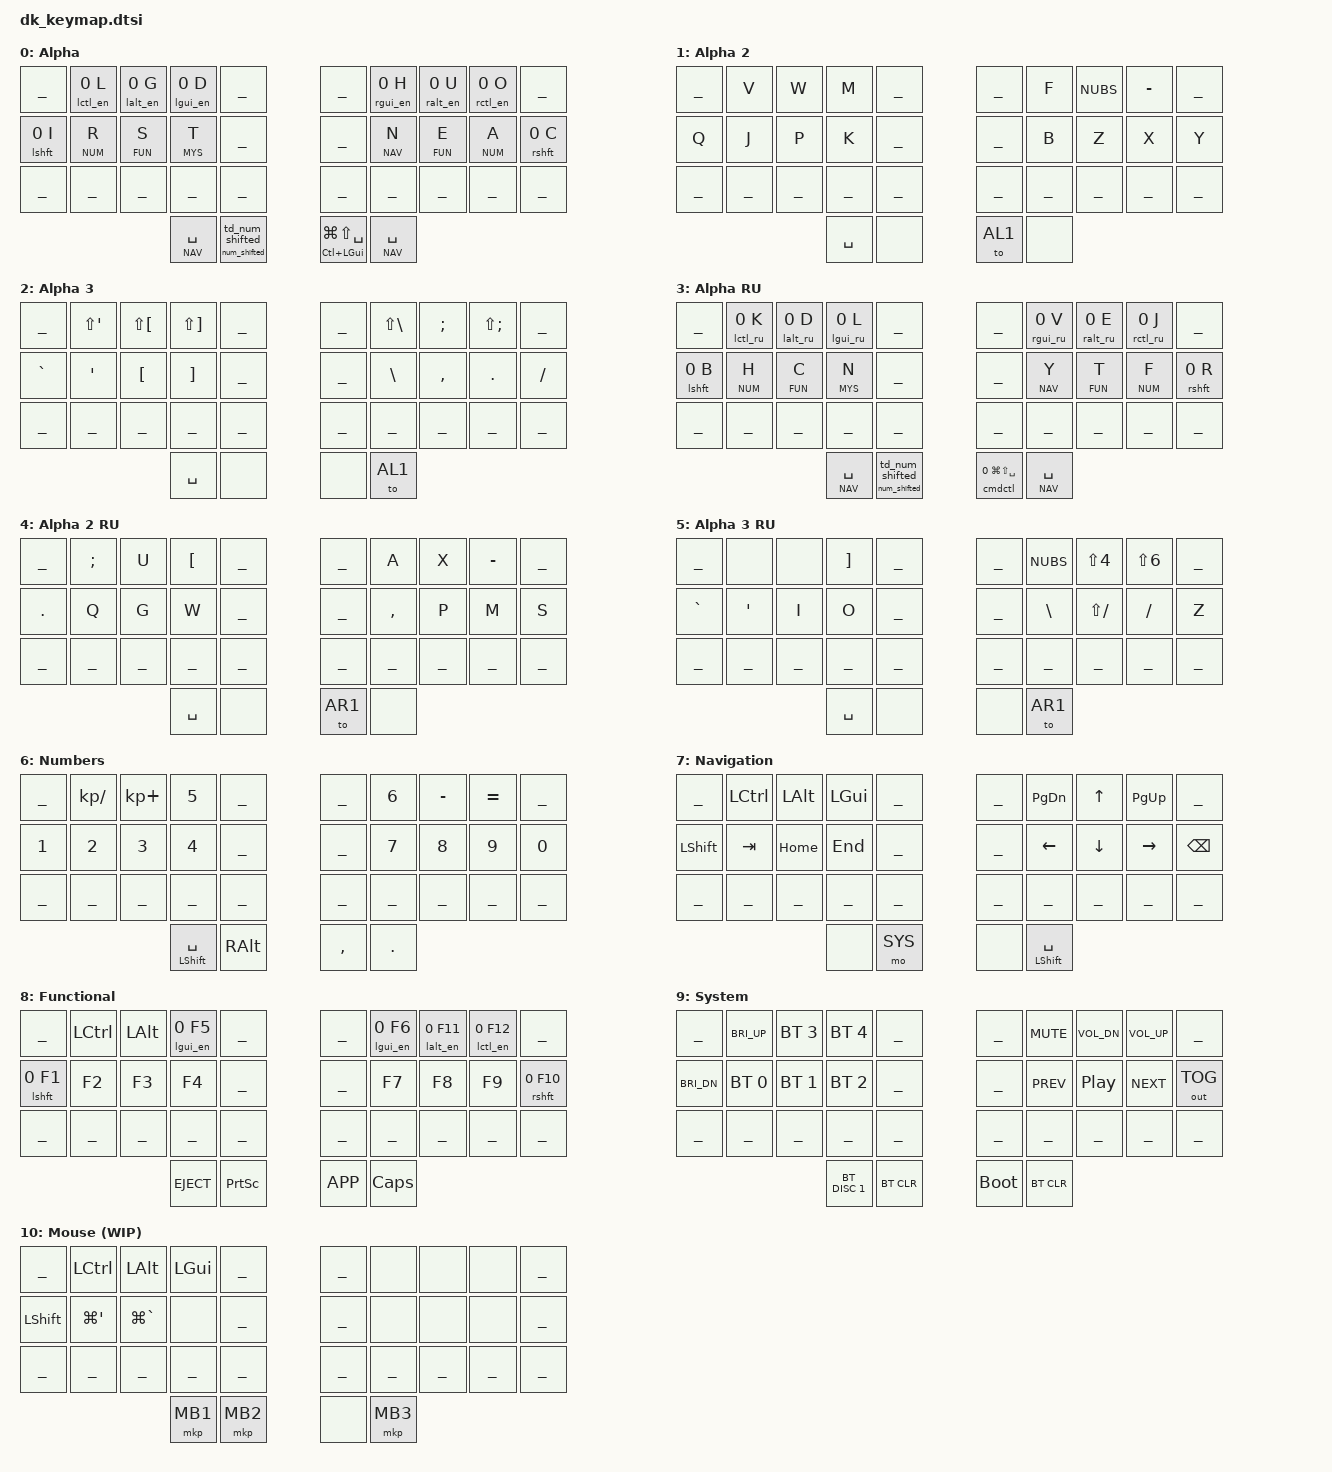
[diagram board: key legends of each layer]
/*
* Copyright (c) 2020 The ZMK Contributors
*
* SPDX-License-Identifier: MIT
*/

#include <behaviors.dtsi>
#include <dt-bindings/zmk/bt.h>
#include <dt-bindings/zmk/keys.h>
#include <dt-bindings/zmk/mouse.h>
#include <dt-bindings/zmk/outputs.h>

// Layers
#define AL1   0
#define AL2   1
#define AL3   2
#define AR1   3
#define AR2   4
#define AR3   5
#define NUM   6
#define NAV   7
#define FUN   8
#define SYS   9
#define MYS  10

#define TAPPING_TERM    300  // tapping-term-ms = <300>;
#define QUICK_TAP_TERM  250  // tapping-term-ms = <300>;
#define COMBO_TIMEOUT_2  50  // timeout-ms for 2 fingers cofbos
#define COMBO_TIMEOUT_3  80  // timeout-ms for 2 fingers combos

#define COMBO(NAME, BINDINGS, KEYPOS, LAYERS) \
  combo_##NAME { \
    timeout-ms = <65>; \
    bindings = <BINDINGS>; \
    key-positions = <KEYPOS>; \
    layers = <LAYERS>; \
  };
#define ONESHOT_LAYER_MACRO(name, layer)                \
name: name##_oneshot_macro {                            \
    compatible = "zmk,behavior-macro";                  \
    #binding-cells = <0>;                               \
    wait-ms = <0>;                                      \
    bindings = <&sl layer>;                             \
};
#define LAT_MOD_MACRO(name, mod, base_layer, mod_layer) \
name: name##_macro {                                    \
	compatible = "zmk,behavior-macro";              \
	#binding-cells = <0>;                           \
	wait-ms = <0>;                                  \
    bindings                                            \
        = <&macro_press &kp mod>                        \
        , <&macro_tap &to mod_layer>                    \
        , <&macro_pause_for_release>                    \
        , <&macro_tap &to base_layer>                   \
        , <&macro_release &kp mod>;                     \
 };
#define MOD_MACRO(name, mod)                            \
name: name##_macro {                                    \
	compatible = "zmk,behavior-macro";              \
	#binding-cells = <0>;                           \
	wait-ms = <0>;                                  \
    bindings                                            \
        = <&macro_press &kp mod>                        \
        , <&macro_pause_for_release>                    \
        , <&macro_release &kp mod>;                     \
 };
#define HOME_ROW_MOD_TAP_LEFT(name, macro, flavortype)  \
name: name##_mod_tap_lefthand {                         \
    compatible = "zmk,behavior-hold-tap";               \
    #binding-cells = <2>;                               \
    flavor = #flavortype;                               \
    tapping-term-ms = <TAPPING_TERM>;                   \
    quick-tap-ms = <QUICK_TAP_TERM>;                    \
    bindings = <macro>, <&kp>;                          \
    hold-trigger-key-positions = < RIGHT_HALF THUMBS >; \
};
#define HOME_ROW_MOD_TAP_RIGHT(name, macro, flavortype) \
name: name##_mod_tap_righthand {                        \
    compatible = "zmk,behavior-hold-tap";               \
    #binding-cells = <2>;                               \
    flavor = #flavortype;                               \
    tapping-term-ms = <TAPPING_TERM>;                   \
    quick-tap-ms = <QUICK_TAP_TERM>;                    \
    bindings = <macro>, <&kp>;                          \
    hold-trigger-key-positions = < LEFT_HALF THUMBS >;  \
};
#define HOME_ROW_MOD_TAP(name, macro, flavortype) \
name: name##_mod_tap_righthand {                        \
    compatible = "zmk,behavior-hold-tap";               \
    #binding-cells = <2>;                               \
    flavor = #flavortype;                               \
    tapping-term-ms = <TAPPING_TERM>;                   \
    quick-tap-ms = <QUICK_TAP_TERM>;                    \
    bindings = <macro>, <&kp>;                          \
};


/ {
combos {
    compatible = "zmk,combos";
    lock               { key-positions = < KEY_L KEY_G KEY_D >; bindings = <&lock>;             timeout-ms = < COMBO_TIMEOUT_2 >; layers = < AL1 AR1 >; };
    to_eng             { key-positions = < KEY_R KEY_S KEY_T >; bindings = <&eng>;              timeout-ms = < COMBO_TIMEOUT_3 >; layers = < AL1 AR1 >; };
    to_rus             { key-positions = < KEY_N KEY_E KEY_A >; bindings = <&rus>;              timeout-ms = < COMBO_TIMEOUT_3 >; layers = < AL1 AR1 >; };
    toggle_device      { key-positions = < KEY_H KEY_U KEY_O >; bindings = <&bt BT_SEL 255>;    timeout-ms = < COMBO_TIMEOUT_3 >; layers = < AL1 AR1 >; };
    studio_unlock      { key-positions = < KEY_H KEY_U KEY_O >; bindings = <&studio_unlock>;    timeout-ms = < COMBO_TIMEOUT_3 >; layers = < FUN >; };


    shift_lock         { key-positions = < KEY_G KEY_S >;       bindings = <&kt LSHFT>;         timeout-ms = < COMBO_TIMEOUT_2 >; layers = < AL1 AR1 >; };
    hyper_left         { key-positions = < KEY_S KEY_T >;       bindings = <&sk LS(LA(LG(LCTRL)))>; timeout-ms = < COMBO_TIMEOUT_2 >; layers = < AL1 AR1 >; };
    hyper_right        { key-positions = < KEY_N KEY_E >;       bindings = <&sk LS(LA(LG(LCTRL)))>; timeout-ms = < COMBO_TIMEOUT_2 >; layers = < AL1 AR1 >; };

    copy_cut           { key-positions = < KEY_R KEY_T >;       bindings = <&td_copy_cut>;      timeout-ms = < COMBO_TIMEOUT_2 >; layers = < AL1 AR1 >; };
    paste              { key-positions = < KEY_L KEY_D >;       bindings = <&kp LG(V)>;         timeout-ms = < COMBO_TIMEOUT_2 >; layers = < AL1 AR1 >; };
    undo               { key-positions = < KEY_I KEY_T >;       bindings = <&kp LG(Z)>;         timeout-ms = < COMBO_TIMEOUT_2 >; layers = < AL1 AR1 >; };
    redo               { key-positions = < KEY_I KEY_T >;       bindings = <&kp LS(LG(Z))>;     timeout-ms = < COMBO_TIMEOUT_3 >; layers = < FUN >; };

    escape_left        { key-positions = < KEY_L KEY_G >;       bindings = <&kp ESC>;           timeout-ms = < COMBO_TIMEOUT_2 >; };
    escape_right       { key-positions = < KEY_U KEY_O >;       bindings = <&kp ESC>;           timeout-ms = < COMBO_TIMEOUT_2 >; };
    enter_left         { key-positions = < KEY_R KEY_S >;       bindings = <&kp ENTER>;         timeout-ms = < COMBO_TIMEOUT_2 >; layers = < AL1 AR1 >; };
    enter_right        { key-positions = < KEY_E KEY_A >;       bindings = <&kp ENTER>;         timeout-ms = < COMBO_TIMEOUT_2 >; layers = < AL1 AR1 NAV >; };
    backspace_left     { key-positions = < KEY_G KEY_T >;       bindings = <&kp BACKSPACE>;     timeout-ms = < COMBO_TIMEOUT_2 >; layers = < AL1 AR1 >; };
    backspace_right    { key-positions = < KEY_N KEY_U >;       bindings = <&kp BACKSPACE>;     timeout-ms = < COMBO_TIMEOUT_2 >; };
    alt_backspace_left { key-positions = < KEY_L KEY_G KEY_T >; bindings = <&kp LA(BACKSPACE)>; timeout-ms = < COMBO_TIMEOUT_3 >; layers = < AL1 AR1 >; };
    alt_backspace_right{ key-positions = < KEY_N KEY_U KEY_O >; bindings = <&kp LA(BACKSPACE)>; timeout-ms = < COMBO_TIMEOUT_3 >; layers = < AL1 AR1 >; };
    delete_left        { key-positions = < KEY_G KEY_R >;       bindings = <&kp DEL>;           timeout-ms = < COMBO_TIMEOUT_2 >; layers = < AL1 AR1 >; };
    delete_right       { key-positions = < KEY_U KEY_A >;       bindings = <&kp DEL>;           timeout-ms = < COMBO_TIMEOUT_2 >; layers = < AL1 AR1 >; };
    tab_left           { key-positions = < KEY_G KEY_D >;       bindings = <&kp TAB>;           timeout-ms = < COMBO_TIMEOUT_2 >; layers = < AL1 AR1 >; };
    tab_right          { key-positions = < KEY_H KEY_U >;       bindings = <&kp TAB>;           timeout-ms = < COMBO_TIMEOUT_2 >; layers = < AL1 AR1 >; };

    COMBO(al2_l, &kp V, 	    KEY_L THUMB_LL, AL1)
    COMBO(al2_g, &kp W, 	    KEY_G THUMB_LL, AL1)
    COMBO(al2_d, &kp M, 	    KEY_D THUMB_LL, AL1)
    COMBO(al2_i, &kp Q, 	    KEY_I THUMB_LL, AL1)
    COMBO(al2_r, &kp J, 	    KEY_R THUMB_LL, AL1)
    COMBO(al2_s, &kp P, 	    KEY_S THUMB_LL, AL1)
    COMBO(al2_t, &kp K, 	    KEY_T THUMB_LL, AL1)

    COMBO(al2_h, &kp F,		    KEY_H THUMB_RR, AL1)
    COMBO(al2_u, &kp NUBS,	    KEY_U THUMB_RR, AL1)
    COMBO(al2_o, &kp MINUS,	    KEY_O THUMB_RR, AL1)
    COMBO(al2_n, &kp B,		    KEY_N THUMB_RR, AL1)
    COMBO(al2_e, &kp Z,		    KEY_E THUMB_RR, AL1)
    COMBO(al2_a, &kp X,		    KEY_A THUMB_RR, AL1)
    COMBO(al2_c, &kp Y,		    KEY_C THUMB_RR, AL1)

    COMBO(al3_l, &kp LS(SQT), 	KEY_L THUMB_LR, AL1)
    COMBO(al3_g, &kp LS(LBKT), 	KEY_G THUMB_LR, AL1)
    COMBO(al3_d, &kp LS(RBKT), 	KEY_D THUMB_LR, AL1)
    COMBO(al3_i, &kp GRAVE, 	KEY_I THUMB_LR, AL1)
    COMBO(al3_r, &kp SQT, 	    KEY_R THUMB_LR, AL1)
    COMBO(al3_s, &kp LBKT, 	    KEY_S THUMB_LR, AL1)
    COMBO(al3_t, &kp RBKT, 	    KEY_T THUMB_LR, AL1)

    COMBO(al3_h, &kp LS(BSLH),	KEY_H THUMB_RL, AL1)
    COMBO(al3_u, &kp SEMI,	    KEY_U THUMB_RL, AL1)
    COMBO(al3_o, &kp LS(SEMI),	KEY_O THUMB_RL, AL1)
    COMBO(al3_n, &kp BSLH,	    KEY_N THUMB_RL, AL1)
    COMBO(al3_e, &kp COMMA,	    KEY_E THUMB_RL, AL1)
    COMBO(al3_a, &kp DOT,	    KEY_A THUMB_RL, AL1)
    COMBO(al3_c, &kp FSLH,	    KEY_C THUMB_RL, AL1)

    COMBO(ar2_l, &kp SEMI,	    KEY_L THUMB_LL, AR1)
    COMBO(ar2_g, &kp U,		    KEY_G THUMB_LL, AR1)
    COMBO(ar2_d, &kp LBKT,	    KEY_D THUMB_LL, AR1)
    COMBO(ar2_i, &kp DOT,	    KEY_I THUMB_LL, AR1)
    COMBO(ar2_r, &kp Q,		    KEY_R THUMB_LL, AR1)
    COMBO(ar2_s, &kp G,		    KEY_S THUMB_LL, AR1)
    COMBO(ar2_t, &kp W,		    KEY_T THUMB_LL, AR1)

    COMBO(ar2_h, &kp A,		    KEY_H THUMB_RR, AR1)
    COMBO(ar2_u, &kp X,		    KEY_U THUMB_RR, AR1)
    COMBO(ar2_o, &kp MINUS,	    KEY_O THUMB_RR, AR1)
    COMBO(ar2_n, &kp COMMA,	    KEY_N THUMB_RR, AR1)
    COMBO(ar2_e, &kp P,		    KEY_E THUMB_RR, AR1)
    COMBO(ar2_a, &kp M,		    KEY_A THUMB_RR, AR1)
    COMBO(ar2_c, &kp S,		    KEY_C THUMB_RR, AR1)

    COMBO(ar3_l, &kp LS(N2),    KEY_L THUMB_LR, AR1)
    COMBO(ar3_g, &kp LA(O),	    KEY_G THUMB_LR, AR1)
    COMBO(ar3_d, &kp RBKT,	    KEY_D THUMB_LR, AR1)
    COMBO(ar3_i, &kp GRAVE,	    KEY_I THUMB_LR, AR1)
    COMBO(ar3_r, &kp SQT,	    KEY_R THUMB_LR, AR1)
    COMBO(ar3_s, &kp I,		    KEY_S THUMB_LR, AR1)
    COMBO(ar3_t, &kp O,		    KEY_T THUMB_LR, AR1)

    COMBO(ar3_h, &kp NUBS,	    KEY_H THUMB_RL, AR1)
    COMBO(ar3_u, &kp LS(N4),    KEY_U THUMB_RL, AR1)
    COMBO(ar3_o, &kp LS(N6),    KEY_O THUMB_RL, AR1)
    COMBO(ar3_n, &kp BSLH,	    KEY_N THUMB_RL, AR1)
    COMBO(ar3_e, &kp LS(FSLH),	KEY_E THUMB_RL, AR1)
    COMBO(ar3_a, &kp FSLH,	    KEY_A THUMB_RL, AR1)
    COMBO(ar3_c, &kp Z,		    KEY_C THUMB_RL, AR1)

};

macros {
    num_shifted: num_shifted {
        compatible = "zmk,behavior-macro";
        #binding-cells = <0>;
        bindings =
            <&macro_press &kp LSHFT &mo NUM >,
            <&macro_pause_for_release>,
            <&macro_release &mo NUM &kp LSHFT>;
        };
    lock: lock {
        compatible = "zmk,behavior-macro";
        #binding-cells = <0>;
        bindings = <&eng &kp LC(LG(Q))>;
    };
    eng: eng {
        compatible = "zmk,behavior-macro";
        #binding-cells = <0>;
        bindings = < &kp F18 &to AL1 >;
        };
    rus: rus {
        compatible = "zmk,behavior-macro";
        #binding-cells = <0>;
        bindings = < &kp F19 &to AR1 >;
        };
    ONESHOT_LAYER_MACRO(sl_al2, AL2)
    ONESHOT_LAYER_MACRO(sl_al3, AL3)
    ONESHOT_LAYER_MACRO(sl_ar2, AR2)
    ONESHOT_LAYER_MACRO(sl_ar3, AR3)

    LAT_MOD_MACRO(alt_ru, LALT, AR1, AL1)
    LAT_MOD_MACRO(gui_ru, LGUI, AR1, AL1)
    LAT_MOD_MACRO(ctl_ru, LCTRL, AR1, AL1)
    LAT_MOD_MACRO(cmdctl_ru, LC(LGUI), AR1, AL1)

    MOD_MACRO(alt_en, LALT)
    MOD_MACRO(gui_en, LGUI)
    MOD_MACRO(ctl_en, LCTRL)
    MOD_MACRO(shft,  LSHFT)
};

behaviors {
    HOME_ROW_MOD_TAP_LEFT (lalt_ru, &alt_ru, balanced)
    HOME_ROW_MOD_TAP_LEFT (lgui_ru, &gui_ru, balanced)
    HOME_ROW_MOD_TAP_LEFT (lctl_ru, &ctl_ru, balanced)
    HOME_ROW_MOD_TAP_RIGHT(ralt_ru, &alt_ru, balanced)
    HOME_ROW_MOD_TAP_RIGHT(rgui_ru, &gui_ru, balanced)
    HOME_ROW_MOD_TAP_RIGHT(rctl_ru, &ctl_ru, balanced)

    HOME_ROW_MOD_TAP_LEFT (lalt_en, &alt_en, balanced)
    HOME_ROW_MOD_TAP_LEFT (lgui_en, &gui_en, balanced)
    HOME_ROW_MOD_TAP_LEFT (lctl_en, &ctl_en, balanced)
    HOME_ROW_MOD_TAP_RIGHT(ralt_en, &alt_en, balanced)
    HOME_ROW_MOD_TAP_RIGHT(rgui_en, &gui_en, balanced)
    HOME_ROW_MOD_TAP_RIGHT(rctl_en, &ctl_en, balanced)

    HOME_ROW_MOD_TAP_LEFT(lshft, &shft, balanced)
    HOME_ROW_MOD_TAP_RIGHT(rshft, &shft, balanced)

    HOME_ROW_MOD_TAP(cmdctl, &cmdctl_ru, balanced)

    mol: homerow_layers_left {
        compatible = "zmk,behavior-hold-tap";
        #binding-cells = <2>;
        tapping-term-ms = < TAPPING_TERM >;
        quick-tap-ms = < QUICK_TAP_TERM >;
        // flavor = "tap-preferred";
        flavor = "balanced";
        bindings = <&mo>, <&kp>;
        hold-trigger-key-positions = < RIGHT_HALF THUMBS >;    // <---[[right-hand keys]]
    };
    mor: homerow_layers_right {
        compatible = "zmk,behavior-hold-tap";
        #binding-cells = <2>;
        tapping-term-ms = < TAPPING_TERM >;
        quick-tap-ms = < QUICK_TAP_TERM >;
        // flavor = "tap-preferred";
        flavor = "balanced";
        bindings = <&mo>, <&kp>;
        hold-trigger-key-positions = < LEFT_HALF THUMBS >;    // <---[[left-hand keys]]
    };

    td_copy_cut: tap_dance_copy_cut {
        compatible = "zmk,behavior-tap-dance";
        #binding-cells = <0>;
        tapping-term-ms = <300>;
        bindings = <&kp LG(C)>, <&kp LG(X)>;
    };

    td_num_shifted: tap_dance_num_shifted {
        compatible = "zmk,behavior-tap-dance";
        #binding-cells = <0>;
        tapping-term-ms = <300>;
        bindings = <&num_shifted>, <&mo NUM>;
    };

    mo_num: mo_num_shifted {
        compatible = "zmk,behavior-hold-tap";
        #binding-cells = <2>;
        tapping-term-ms = < TAPPING_TERM >;
        quick-tap-ms = < QUICK_TAP_TERM >;
        flavor = "hold-preferred";
        bindings = <&num_shifted>, <&td_num_shifted>;
    };
};

keymap {
    compatible = "zmk,keymap";

// ======================================================================= ALPHA =======================================================================================
alpha1 {
    display-name = "Alpha";
    bindings = <
    _____             &lctl_en 0 L       &lalt_en 0 G  &lgui_en 0 D  _____            _____        &rgui_en 0 H      &ralt_en 0 U    &rctl_en 0 O     _____
    &lshft 0 I        &mol NUM R         &mol FUN S    &mol MYS T    _____            _____        &mor NAV N        &mor FUN E      &mor NUM A       &rshft 0 C
    _____             _____              _____         _____         _____            _____        _____             _____           _____            _____
                                                       &lt NAV SPC   &mo_num 0 0      &mt LC(LGUI) LG(LS(SPC))  &lt NAV SPC
                                                    //    &lt NAV SPC   &num_shifted     &sl_al3      &sl_al2
    >;
};
alpha2 {
    display-name = "Alpha 2";
    bindings = <
    _____             &kp V              &kp W         &kp M         _____            _____        &kp F             &kp NUBS        &kp MINUS        _____
    &kp Q             &kp J              &kp P         &kp K         _____            _____        &kp B             &kp Z           &kp X            &kp Y
    _____             _____              _____         _____         _____            _____        _____             _____           _____            _____
                                                       &kp SPC       &none            &to AL1      &none
    >;
};
alpha3 {
    display-name = "Alpha 3";
    bindings = <
    _____             &kp LS(SQT)        &kp LS(LBKT)  &kp LS(RBKT)  _____            _____        &kp LS(BSLH)      &kp SEMI        &kp LS(SEMI)     _____
    &kp GRAVE         &kp SQT            &kp LBKT      &kp RBKT      _____            _____        &kp BSLH          &kp COMMA       &kp DOT          &kp FSLH
    _____             _____              _____         _____         _____            _____        _____             _____           _____            _____
                                                       &kp SPC       &none            &none        &to AL1
    >;
};

// ======================================================================= ALPHA RUS =======================================================================================

alpha1rus {
    display-name = "Alpha RU";
    bindings = <
    _____             &lctl_ru 0 K       &lalt_ru 0 D  &lgui_ru 0 L _____            _____        &rgui_ru 0 V      &ralt_ru 0 E    &rctl_ru 0 J     _____
    &lshft 0 B        &mol NUM H         &mol FUN C    &mol MYS N   _____            _____        &mor NAV Y        &mor FUN T      &mor NUM F       &rshft 0 R
    _____             _____              _____         _____        _____            _____        _____             _____           _____            _____
                                                       &lt NAV SPC  &mo_num 0 0      &cmdctl 0 LG(LS(SPC))  &lt NAV SPC
                                                    //    &lt NAV SPC   &num_shifted     &sl_ar3      &sl_ar2
    >;
};
alpha2rus {
    display-name = "Alpha 2 RU";
    bindings = <
    _____             &kp SEMI           &kp U         &kp LBKT      _____            _____        &kp A             &kp X           &kp MINUS        _____
    &kp DOT           &kp Q              &kp G         &kp W         _____            _____        &kp COMMA         &kp P           &kp M            &kp S
    _____             _____              _____         _____         _____            _____        _____             _____           _____            _____
                                                       &kp SPC       &none            &to AR1      &none
    >;
};
alpha3rus {
    display-name = "Alpha 3 RU";
    bindings = <
    _____             &none              &none         &kp RBKT      _____            _____        &kp NUBS          &kp LS(N4)      &kp LS(N6)       _____
    &kp GRAVE         &kp SQT            &kp I         &kp O         _____            _____        &kp BSLH          &kp LS(FSLH)    &kp FSLH         &kp Z
    _____             _____              _____         _____         _____            _____        _____             _____           _____            _____
                                                       &kp SPC       &none            &none        &to AR1
    >;
};

// ======================================================================= ADDINIONAL =======================================================================================

numbers {
    display-name = "Numbers";
    bindings = <
    _____          &kp KP_DIVIDE     &kp KP_PLUS       &kp N5        _____            _____        &kp N6            &kp MINUS       &kp EQUAL        _____
    &kp N1         &kp N2            &kp N3            &kp N4        _____            _____        &kp N7            &kp N8          &kp N9           &kp N0
    _____          _____             _____             _____         _____            _____        _____             _____           _____            _____
                                                       &mt LSHFT SPC &kp RALT         &kp COMMA    &kp DOT
    >;
};

navigation {
    display-name = "Navigation";
    bindings = <
    _____             &kp LCTL           &kp LALT      &kp LGUI      _____            _____        &kp PG_DN         &kp UP          &kp PG_UP        _____
    &kp LSHFT         &kp TAB            &kp HOME      &kp END       _____            _____        &kp LEFT          &kp DOWN        &kp RIGHT        &kp BACKSPACE
    _____             _____              _____         _____         _____            _____        _____             _____           _____            _____
                                                       &none         &mo SYS          &none        &mt LSHFT SPC
    >;
};

function {
    display-name = "Functional";
    bindings = <
    _____             &kp LCTL           &kp LALT      &lgui_en 0 F5 _____            _____        &lgui_en 0 F6     &lalt_en 0 F11  &lctl_en 0 F12   _____
    &lshft 0 F1       &kp F2             &kp F3        &kp F4        _____            _____        &kp F7            &kp F8          &kp F9           &rshft 0 F10
    _____             _____              _____         _____         _____            _____        _____             _____           _____            _____
                                                       &kp C_EJECT   &kp PRINTSCREEN  &kp K_APP    &kp CAPS
    >;
};

system {
    display-name = "System";
    bindings = <
    _____             &kp C_BRI_UP       &bt BT_SEL 3  &bt BT_SEL 4  _____            _____        &kp C_MUTE        &kp C_VOL_DN    &kp C_VOL_UP     _____
    &kp C_BRI_DN      &bt BT_SEL 0       &bt BT_SEL 1  &bt BT_SEL 2  _____            _____        &kp C_PREV        &kp C_PP        &kp C_NEXT       &out OUT_TOG
    _____             _____              _____         _____         _____            _____        _____             _____           _____            _____
                                                       &bt BT_DISC 1 &bt BT_CLR       &bootloader  &bt BT_CLR
    >;
};

mouse {
    display-name = "Mouse (WIP)";
    bindings = <
    _____             &kp LCTL           &kp LALT      &kp LGUI      _____            _____        &none  &none  &none     _____
    &kp LSHFT         &kp LG(SQT)        &kp LG(GRAVE) &none         _____            _____        &none  &none  &none     _____
    // _____             &kp LCTL           &kp LALT      &kp LGUI      _____            _____        &msc SCRL_DOWN    &mmv MOVE_UP    &msc SCRL_UP     _____
    // &kp LSHFT         &kp LG(SQT)        &kp LG(GRAVE) &none         _____            _____        &mmv MOVE_LEFT    &mmv MOVE_DOWN  &mmv MOVE_RIGHT  &none
    _____             _____              _____         _____         _____            _____        _____             _____           _____            _____
                                                       &mkp MB1      &mkp MB2         &none        &mkp MB3
    >;
};

    };
};
